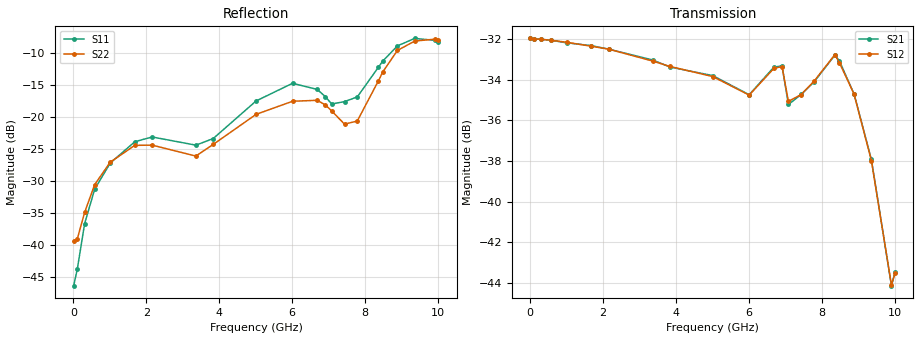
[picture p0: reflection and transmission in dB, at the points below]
! Device ID: PE43705
! Serial: 1
! Insertion: A
! Impedance: 50 ohm
! Temp: 25C
! VDD: 3.400V
! Attenuation Step: 31.00dB
#  Hz  S  RI  R  50
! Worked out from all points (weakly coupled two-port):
!   401 points, 10 MHz to 10.01 GHz, reference 50 ohm
!   highest |S21| = -31.96 dB at 10 MHz (marker M1); lowest = -44.1 dB at 9.91 GHz (marker M2)
!   lowest |S11| = -46.4 dB at 10 MHz (marker M3), VSWR 1.01, Z = 49.5 + j0.0442 ohm
!   |S11| at or under -10 dB: start of sweep to 8.673 GHz
!   |S22| runs from -39.6 to -7.8 dB; largest |S21 - S12| = 0.00059
!   S11 on the Smith chart (normalised r, x): 10 MHz: 0.99, +0.00; 7.435 GHz: 0.82, +0.16; 8.485 GHz: 0.84, +0.49; 9.36 GHz: 0.55, +0.49; 10.01 GHz: 0.49, +0.27
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1e7  -0.00476 0.000446  0.0252 -7.93e-05  0.0252 -9.19e-05  -0.0106 0.00055
1.1e8  -0.00442 0.00471  0.0251 -0.000651  0.0251 -0.000633  -0.00984 0.00517
3.1e8  -0.00681 0.0129  0.025 -0.00181  0.025 -0.00185  -0.0116 0.0136
5.85e8  -0.0147 0.0228  0.0247 -0.00332  0.0247 -0.00334  -0.0179 0.0234
1.01e9  -0.0336 0.0275  0.0239 -0.00569  0.024 -0.00561  -0.0334 0.0288
1.685e9  -0.0613 0.0177  0.0225 -0.00887  0.0224 -0.00889  -0.0553 0.0227
2.16e9  -0.0694 0.00431  0.021 -0.011  0.021 -0.011  -0.0586 0.0131
3.36e9  -0.0598 0.00491  0.0166 -0.0149  0.0165 -0.0148  -0.0467 0.0158
3.835e9  -0.0622 0.0264  0.0148 -0.0155  0.0148 -0.0156  -0.0538 0.0283
5.01e9  -0.0992 0.0885  0.0116 -0.0168  0.0114 -0.0168  -0.0867 0.0582
6.01e9  -0.1511 0.1026  0.00797 -0.0165  0.00787 -0.0165  -0.1155 0.0644
6.685e9  -0.1415 0.0825  0.00709 -0.0202  0.0072 -0.02  -0.1239 0.0524
6.91e9  -0.123 0.0743  0.00406 -0.0212  0.00408 -0.0211  -0.1136 0.0492
7.085e9  -0.1079 0.0647  0.00217 -0.0172  0.00223 -0.0175  -0.0981 0.0521
7.435e9  -0.0891 0.0966  0.00403 -0.0179  0.00401 -0.0179  -0.0659 0.0577
7.785e9  -0.043 0.1363  0.00434 -0.0192  0.00427 -0.0193  -0.0428 0.0822
8.36e9  -0.00896 0.2427  -0.00313 -0.0227  -0.00291 -0.0228  -0.0363 0.1864
8.485e9  -0.0149 0.2724  -0.00538 -0.0215  -0.00524 -0.0213  -0.0452 0.2196
8.885e9  -0.0682 0.3515  -0.00925 -0.0159  -0.00924 -0.0159  -0.1083 0.3117
9.36e9  -0.1715 0.3727  -0.00841 -0.00952  -0.00824 -0.00957  -0.2136 0.3272
9.91e9  -0.2896 0.27  -0.000935 -0.00615  -0.00108 -0.00615  -0.3502 0.2025
1.001e10  -0.3024 0.2365  -1.94e-05 -0.00672  0.000286 -0.00668  -0.3667 0.1631
